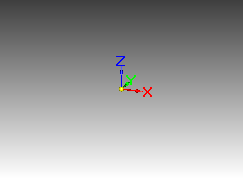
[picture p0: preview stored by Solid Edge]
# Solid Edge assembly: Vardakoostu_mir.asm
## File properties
Author: Türk
Template: Iso Assembly.asm
Last saved by: Türk
Revision: 3
Application: Solid Edge
Username: Türk
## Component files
Poldikoostu3_mir.asm
Vedrustuse varras.par
